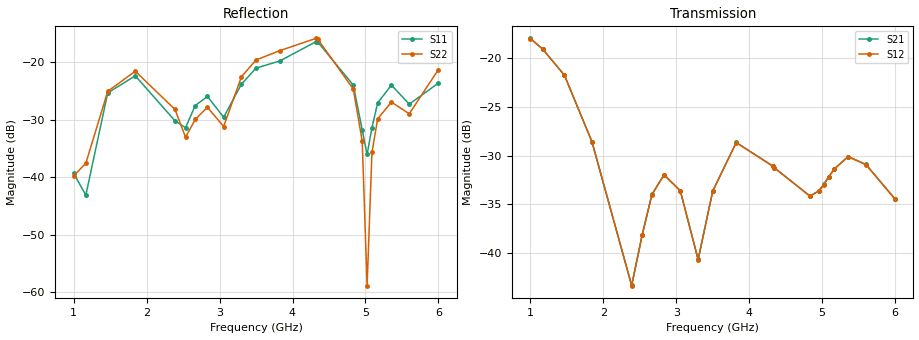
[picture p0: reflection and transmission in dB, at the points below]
!Agilent Technologies,E8364B,MY43040528,A.07.50.67
!Agilent E8364B: A.07.50.67
!Date: Sunday, March 01, 2026 20:57:26
!Correction: S11(Full 2 Port(1,2))
!S21(Full 2 Port(1,2))
!S12(Full 2 Port(1,2))
!S22(Full 2 Port(1,2))
!S2P File: Measurements: S11, S21, S12, S22:
# Hz S  dB  R 50
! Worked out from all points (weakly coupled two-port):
!   451 points, 1 GHz to 6 GHz, reference 50 ohm
!   highest |S21| = -17.95 dB at 1 GHz (marker M1); lowest = -43.3 dB at 2.389 GHz (marker M2)
!   lowest |S11| = -43.1 dB at 1.167 GHz (marker M3), VSWR 1.01, Z = 49.5 + j0.49 ohm
!   |S11| at or under -10 dB: start of sweep to end of sweep
!   |S22| runs from -58.9 to -15.6 dB; largest |S21 - S12| = 0.00042
!   S11 on the Smith chart (normalised r, x): 1 GHz: 1.01, +0.02; 4.322 GHz: 1.24, -0.24; 6 GHz: 0.99, -0.13
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1e9  -39.34 65.0  -17.95 25.5  -17.97 25.5  -39.75 33.6
1.166667e9  -43.12 134.9  -19.02 -24.6  -19.05 -24.7  -37.58 72.5
1.466667e9  -25.34 161.8  -21.72 -125.2  -21.74 -125.2  -25.07 80.4
1.844444e9  -22.36 93.8  -28.55 115.8  -28.57 115.8  -21.56 -5.1
2.388889e9  -30.19 49.4  -43.31 -120.0  -43.34 -120.0  -28.22 -91.2
2.533333e9  -31.38 79.2  -38.11 125.0  -38.13 125.0  -33.03 -76.9
2.666667e9  -27.54 83.0  -33.96 59.0  -33.99 59.0  -29.96 -57.7
2.833333e9  -25.95 61.8  -31.94 -12.1  -31.98 -12.1  -27.83 -79.8
3.055556e9  -29.57 56.9  -33.58 -98.2  -33.62 -98.2  -31.19 -74.3
3.3e9  -23.82 76.4  -40.64 -134.1  -40.67 -134.1  -22.51 -74.7
3.5e9  -21.02 50.5  -33.61 -155.0  -33.65 -155.0  -19.61 -111.6
3.822222e9  -19.80 26.3  -28.63 87.1  -28.66 87.1  -18.00 -153.8
4.322222e9  -16.43 -38.7  -31.04 -94.3  -31.08 -94.3  -15.85 116.3
4.344444e9  -16.46 -42.2  -31.22 -102.2  -31.25 -102.1  -15.97 111.6
4.833333e9  -23.98 -122.5  -34.13 41.7  -34.16 41.7  -24.68 -2.0
4.955556e9  -31.77 -124.3  -33.59 -27.8  -33.61 -27.8  -33.75 -37.8
5.022222e9  -36.05 -81.5  -32.93 -64.9  -32.96 -64.9  -58.87 -127.6
5.088889e9  -31.39 -49.1  -32.18 -100.4  -32.21 -100.4  -35.69 114.1
5.166667e9  -27.09 -49.6  -31.34 -139.7  -31.38 -139.7  -29.86 90.4
5.355556e9  -23.97 -79.1  -30.08 132.5  -30.11 132.5  -26.94 45.2
5.6e9  -27.30 -99.1  -30.88 31.0  -30.92 31.0  -28.97 36.5
6e9  -23.63 -90.7  -34.44 -84.3  -34.47 -84.3  -21.27 -4.3
